VERSION 5.7 ;
  NOWIREEXTENSIONATPIN ON ;
  DIVIDERCHAR "/" ;
  BUSBITCHARS "[]" ;
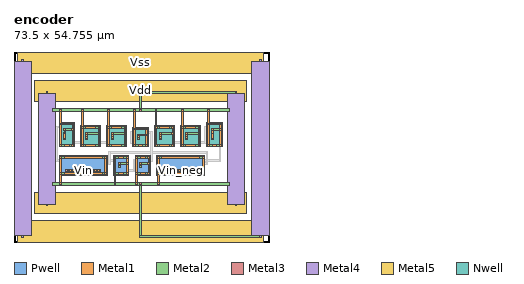
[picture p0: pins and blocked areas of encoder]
MACRO encoder
  CLASS BLOCK ;
  FOREIGN encoder ;
  ORIGIN 0.000 0.000 ;
  SIZE 73.500 BY 54.755 ;
  PIN Vss
    USE GROUND;
    ANTENNADIFFAREA 37.930798 ;
    PORT
      LAYER Pwell ;
        RECT 13.000 19.260 26.860 24.860 ;
        RECT 28.660 19.260 33.100 24.860 ;
        RECT 34.900 19.260 39.340 24.860 ;
        RECT 41.140 19.260 55.000 24.860 ;
      LAYER Metal1 ;
        RECT 13.230 24.150 13.730 24.650 ;
        RECT 14.480 24.150 25.380 24.650 ;
        RECT 26.130 24.150 26.630 24.650 ;
        RECT 13.230 19.970 13.690 24.150 ;
        RECT 26.170 19.970 26.630 24.150 ;
        RECT 13.230 19.470 13.730 19.970 ;
        RECT 14.480 19.470 25.380 19.970 ;
        RECT 26.130 19.470 26.630 19.970 ;
        RECT 28.890 24.150 29.390 24.650 ;
        RECT 30.230 24.150 31.530 24.650 ;
        RECT 32.370 24.150 32.870 24.650 ;
        RECT 28.890 19.970 29.350 24.150 ;
        RECT 32.410 22.955 32.870 24.150 ;
        RECT 30.060 22.455 30.560 22.955 ;
        RECT 32.370 22.455 32.870 22.955 ;
        RECT 30.080 21.905 30.540 22.455 ;
        RECT 30.060 21.405 30.560 21.905 ;
        RECT 32.410 19.970 32.870 22.455 ;
        RECT 28.890 19.470 29.390 19.970 ;
        RECT 30.230 19.470 31.530 19.970 ;
        RECT 32.370 19.470 32.870 19.970 ;
        RECT 35.130 24.150 35.630 24.650 ;
        RECT 36.470 24.150 37.770 24.650 ;
        RECT 38.610 24.150 39.110 24.650 ;
        RECT 35.130 19.970 35.590 24.150 ;
        RECT 38.650 22.955 39.110 24.150 ;
        RECT 36.300 22.455 36.800 22.955 ;
        RECT 38.610 22.455 39.110 22.955 ;
        RECT 36.320 21.905 36.780 22.455 ;
        RECT 36.300 21.405 36.800 21.905 ;
        RECT 38.650 19.970 39.110 22.455 ;
        RECT 35.130 19.470 35.630 19.970 ;
        RECT 36.470 19.470 37.770 19.970 ;
        RECT 38.610 19.470 39.110 19.970 ;
        RECT 41.370 24.150 41.870 24.650 ;
        RECT 42.620 24.150 53.520 24.650 ;
        RECT 54.270 24.150 54.770 24.650 ;
        RECT 41.370 19.970 41.830 24.150 ;
        RECT 54.310 19.970 54.770 24.150 ;
        RECT 41.370 19.470 41.870 19.970 ;
        RECT 42.620 19.470 53.520 19.970 ;
        RECT 54.270 19.470 54.770 19.970 ;
        RECT 13.230 17.010 13.690 19.470 ;
        RECT 28.890 17.010 29.350 19.470 ;
        RECT 35.130 17.010 35.590 19.470 ;
        RECT 41.370 17.010 41.830 19.470 ;
        RECT 13.230 16.510 13.730 17.010 ;
        RECT 28.890 16.510 29.390 17.010 ;
        RECT 35.130 16.510 35.630 17.010 ;
        RECT 41.330 16.510 41.830 17.010 ;
      LAYER Metal2 ;
        RECT 2.250 52.005 2.750 52.505 ;
        RECT 70.750 52.005 71.250 52.505 ;
        RECT 13.230 24.150 26.630 24.650 ;
        RECT 28.890 24.150 32.870 24.650 ;
        RECT 35.130 24.150 39.110 24.650 ;
        RECT 41.370 24.150 54.770 24.650 ;
        RECT 30.060 22.455 32.870 22.955 ;
        RECT 36.300 22.455 39.110 22.955 ;
        RECT 30.060 21.405 30.560 21.905 ;
        RECT 36.300 21.405 36.800 21.905 ;
        RECT 13.230 19.470 26.630 19.970 ;
        RECT 28.890 19.470 32.870 19.970 ;
        RECT 35.130 19.470 39.110 19.970 ;
        RECT 41.370 19.470 54.770 19.970 ;
        RECT 11.000 16.260 62.000 17.260 ;
        RECT 36.250 1.750 36.750 16.260 ;
        RECT 2.250 1.250 2.750 1.750 ;
        RECT 36.250 1.250 71.250 1.750 ;
      LAYER Metal3 ;
        RECT 2.250 52.005 2.750 52.505 ;
        RECT 70.750 52.005 71.250 52.505 ;
        RECT 36.250 16.510 36.750 17.010 ;
        RECT 2.250 1.250 2.750 1.750 ;
        RECT 70.750 1.250 71.250 1.750 ;
      LAYER Metal4 ;
        RECT 2.250 52.005 2.750 52.505 ;
        RECT 70.750 52.005 71.250 52.505 ;
        RECT 0.000 1.750 5.000 52.005 ;
        RECT 68.500 1.750 73.500 52.005 ;
        RECT 2.250 1.250 2.750 1.750 ;
        RECT 70.750 1.250 71.250 1.750 ;
      LAYER Metal5 ;
        RECT 1.000 48.625 72.000 54.755 ;
        RECT 1.000 0.000 72.000 6.130 ;
    END
  END Vss
  PIN Vdd
    USE POWER;
    ANTENNADIFFAREA 54.005398 ;
    PORT
      LAYER Nwell ;
        RECT 13.000 27.405 17.440 34.495 ;
        RECT 19.240 27.405 24.960 33.435 ;
        RECT 26.760 27.405 32.480 33.435 ;
        RECT 34.280 27.405 38.720 33.005 ;
        RECT 40.520 27.405 46.240 33.435 ;
        RECT 48.040 27.405 53.760 33.435 ;
        RECT 55.560 27.405 60.000 34.495 ;
      LAYER Metal1 ;
        RECT 13.230 37.745 13.730 38.245 ;
        RECT 19.470 37.745 19.970 38.245 ;
        RECT 26.990 37.745 27.490 38.245 ;
        RECT 34.510 37.745 35.010 38.245 ;
        RECT 40.710 37.745 41.210 38.245 ;
        RECT 48.230 37.745 48.730 38.245 ;
        RECT 55.750 37.745 56.250 38.245 ;
        RECT 13.230 34.285 13.690 37.745 ;
        RECT 13.230 33.785 13.730 34.285 ;
        RECT 14.570 33.785 15.870 34.285 ;
        RECT 16.710 33.785 17.210 34.285 ;
        RECT 13.230 28.115 13.690 33.785 ;
        RECT 16.750 32.595 17.210 33.785 ;
        RECT 14.400 32.095 14.900 32.595 ;
        RECT 16.710 32.095 17.210 32.595 ;
        RECT 14.420 31.195 14.880 32.095 ;
        RECT 14.400 29.895 14.900 31.195 ;
        RECT 14.420 29.545 14.880 29.895 ;
        RECT 16.750 28.115 17.210 32.095 ;
        RECT 13.230 27.615 13.730 28.115 ;
        RECT 14.570 27.615 15.870 28.115 ;
        RECT 16.710 27.615 17.210 28.115 ;
        RECT 19.470 33.225 19.930 37.745 ;
        RECT 26.990 33.225 27.450 37.745 ;
        RECT 19.470 32.725 19.970 33.225 ;
        RECT 20.650 32.725 23.550 33.225 ;
        RECT 24.230 32.725 24.730 33.225 ;
        RECT 19.470 28.115 19.930 32.725 ;
        RECT 24.270 31.535 24.730 32.725 ;
        RECT 20.640 31.035 21.140 31.535 ;
        RECT 24.230 31.035 24.730 31.535 ;
        RECT 20.660 30.270 21.120 31.035 ;
        RECT 20.640 29.770 21.140 30.270 ;
        RECT 20.660 29.555 21.120 29.770 ;
        RECT 24.270 28.115 24.730 31.035 ;
        RECT 19.470 27.615 19.970 28.115 ;
        RECT 20.650 27.615 23.550 28.115 ;
        RECT 24.230 27.615 24.730 28.115 ;
        RECT 26.990 32.725 27.490 33.225 ;
        RECT 28.170 32.725 31.070 33.225 ;
        RECT 31.750 32.725 32.250 33.225 ;
        RECT 26.990 28.115 27.450 32.725 ;
        RECT 31.790 31.535 32.250 32.725 ;
        RECT 28.160 31.035 28.660 31.535 ;
        RECT 31.750 31.035 32.250 31.535 ;
        RECT 28.180 30.270 28.640 31.035 ;
        RECT 28.160 29.770 28.660 30.270 ;
        RECT 28.180 29.555 28.640 29.770 ;
        RECT 31.790 28.115 32.250 31.035 ;
        RECT 26.990 27.615 27.490 28.115 ;
        RECT 28.170 27.615 31.070 28.115 ;
        RECT 31.750 27.615 32.250 28.115 ;
        RECT 34.510 32.795 34.970 37.745 ;
        RECT 40.750 33.225 41.210 37.745 ;
        RECT 48.270 33.225 48.730 37.745 ;
        RECT 55.790 34.285 56.250 37.745 ;
        RECT 55.790 33.785 56.290 34.285 ;
        RECT 57.130 33.785 58.430 34.285 ;
        RECT 59.270 33.785 59.770 34.285 ;
        RECT 34.510 32.295 35.010 32.795 ;
        RECT 35.850 32.295 37.150 32.795 ;
        RECT 37.990 32.295 38.490 32.795 ;
        RECT 34.510 28.115 34.970 32.295 ;
        RECT 38.030 31.100 38.490 32.295 ;
        RECT 35.680 30.600 36.180 31.100 ;
        RECT 37.990 30.600 38.490 31.100 ;
        RECT 35.700 30.050 36.160 30.600 ;
        RECT 35.680 29.550 36.180 30.050 ;
        RECT 38.030 28.115 38.490 30.600 ;
        RECT 34.510 27.615 35.010 28.115 ;
        RECT 35.850 27.615 37.150 28.115 ;
        RECT 37.990 27.615 38.490 28.115 ;
        RECT 40.750 32.725 41.250 33.225 ;
        RECT 41.930 32.725 44.830 33.225 ;
        RECT 45.510 32.725 46.010 33.225 ;
        RECT 40.750 28.115 41.210 32.725 ;
        RECT 45.550 31.535 46.010 32.725 ;
        RECT 41.920 31.035 42.420 31.535 ;
        RECT 45.510 31.035 46.010 31.535 ;
        RECT 41.940 30.270 42.400 31.035 ;
        RECT 41.920 29.770 42.420 30.270 ;
        RECT 41.940 29.555 42.400 29.770 ;
        RECT 45.550 28.115 46.010 31.035 ;
        RECT 40.750 27.615 41.250 28.115 ;
        RECT 41.930 27.615 44.830 28.115 ;
        RECT 45.510 27.615 46.010 28.115 ;
        RECT 48.270 32.725 48.770 33.225 ;
        RECT 49.450 32.725 52.350 33.225 ;
        RECT 53.030 32.725 53.530 33.225 ;
        RECT 48.270 28.115 48.730 32.725 ;
        RECT 53.070 31.535 53.530 32.725 ;
        RECT 49.440 31.035 49.940 31.535 ;
        RECT 53.030 31.035 53.530 31.535 ;
        RECT 49.460 30.270 49.920 31.035 ;
        RECT 49.440 29.770 49.940 30.270 ;
        RECT 49.460 29.555 49.920 29.770 ;
        RECT 53.070 28.115 53.530 31.035 ;
        RECT 48.270 27.615 48.770 28.115 ;
        RECT 49.450 27.615 52.350 28.115 ;
        RECT 53.030 27.615 53.530 28.115 ;
        RECT 55.790 28.115 56.250 33.785 ;
        RECT 59.310 32.595 59.770 33.785 ;
        RECT 56.960 32.095 57.460 32.595 ;
        RECT 59.270 32.095 59.770 32.595 ;
        RECT 56.980 31.195 57.440 32.095 ;
        RECT 56.960 29.895 57.460 31.195 ;
        RECT 56.980 29.545 57.440 29.895 ;
        RECT 59.310 28.115 59.770 32.095 ;
        RECT 55.790 27.615 56.290 28.115 ;
        RECT 57.130 27.615 58.430 28.115 ;
        RECT 59.270 27.615 59.770 28.115 ;
      LAYER Metal2 ;
        RECT 9.250 42.875 9.750 43.375 ;
        RECT 36.250 42.875 64.250 43.375 ;
        RECT 36.250 38.495 36.750 42.875 ;
        RECT 11.000 37.495 62.000 38.495 ;
        RECT 13.230 33.785 17.210 34.285 ;
        RECT 55.790 33.785 59.770 34.285 ;
        RECT 19.470 32.725 24.730 33.225 ;
        RECT 26.990 32.725 32.250 33.225 ;
        RECT 14.400 32.095 17.210 32.595 ;
        RECT 34.510 32.295 38.490 32.795 ;
        RECT 40.750 32.725 46.010 33.225 ;
        RECT 48.270 32.725 53.530 33.225 ;
        RECT 56.960 32.095 59.770 32.595 ;
        RECT 14.400 29.545 14.900 31.545 ;
        RECT 20.640 31.035 24.730 31.535 ;
        RECT 28.160 31.035 32.250 31.535 ;
        RECT 35.680 30.600 38.490 31.100 ;
        RECT 41.920 31.035 46.010 31.535 ;
        RECT 49.440 31.035 53.530 31.535 ;
        RECT 20.640 29.555 21.140 30.485 ;
        RECT 28.160 29.555 28.660 30.485 ;
        RECT 35.680 29.550 36.180 30.050 ;
        RECT 41.920 29.555 42.420 30.485 ;
        RECT 49.440 29.555 49.940 30.485 ;
        RECT 56.960 29.545 57.460 31.545 ;
        RECT 13.230 27.615 17.210 28.115 ;
        RECT 19.470 27.615 24.730 28.115 ;
        RECT 26.990 27.615 32.250 28.115 ;
        RECT 34.510 27.615 38.490 28.115 ;
        RECT 40.750 27.615 46.010 28.115 ;
        RECT 48.270 27.615 53.530 28.115 ;
        RECT 55.790 27.615 59.770 28.115 ;
        RECT 9.250 10.380 9.750 10.880 ;
        RECT 63.750 10.380 64.250 10.880 ;
      LAYER Metal3 ;
        RECT 9.250 42.875 9.750 43.375 ;
        RECT 63.750 42.875 64.250 43.375 ;
        RECT 36.250 37.745 36.750 38.245 ;
        RECT 9.250 10.380 9.750 10.880 ;
        RECT 63.750 10.380 64.250 10.880 ;
      LAYER Metal4 ;
        RECT 9.250 42.875 9.750 43.375 ;
        RECT 63.750 42.875 64.250 43.375 ;
        RECT 7.000 10.875 12.000 42.875 ;
        RECT 61.500 10.875 66.500 42.875 ;
        RECT 9.250 10.380 9.750 10.875 ;
        RECT 63.750 10.380 64.250 10.875 ;
      LAYER Metal5 ;
        RECT 6.000 40.495 67.000 46.625 ;
        RECT 6.000 8.130 67.000 14.260 ;
    END
  END Vdd
  PIN Vin
    ANTENNAGATEAREA 5.000000 ;
    PORT
      LAYER Metal1 ;
        RECT 15.280 20.365 15.780 20.865 ;
        RECT 16.080 20.365 16.580 20.865 ;
        RECT 16.880 20.365 17.380 20.865 ;
        RECT 17.680 20.365 18.180 20.865 ;
        RECT 18.480 20.365 18.980 20.865 ;
        RECT 19.280 20.365 19.780 20.865 ;
        RECT 20.080 20.365 20.580 20.865 ;
        RECT 20.880 20.365 21.380 20.865 ;
        RECT 21.680 20.365 22.180 20.865 ;
        RECT 22.480 20.365 22.980 20.865 ;
        RECT 23.280 20.365 23.780 20.865 ;
        RECT 24.080 20.365 24.580 20.865 ;
      LAYER Metal2 ;
        RECT 14.930 20.365 24.930 20.865 ;
      LAYER Metal3 ;
        RECT 14.930 20.365 15.430 20.865 ;
    END
  END Vin
  PIN Vin_neg
    ANTENNAGATEAREA 5.000000 ;
    PORT
      LAYER Metal1 ;
        RECT 43.420 20.365 43.920 20.865 ;
        RECT 44.220 20.365 44.720 20.865 ;
        RECT 45.020 20.365 45.520 20.865 ;
        RECT 45.820 20.365 46.320 20.865 ;
        RECT 46.620 20.365 47.120 20.865 ;
        RECT 47.420 20.365 47.920 20.865 ;
        RECT 48.220 20.365 48.720 20.865 ;
        RECT 49.020 20.365 49.520 20.865 ;
        RECT 49.820 20.365 50.320 20.865 ;
        RECT 50.620 20.365 51.120 20.865 ;
        RECT 51.420 20.365 51.920 20.865 ;
        RECT 52.220 20.365 52.720 20.865 ;
      LAYER Metal2 ;
        RECT 43.070 20.365 53.070 20.865 ;
      LAYER Metal3 ;
        RECT 43.070 20.365 43.570 20.865 ;
    END
  END Vin_neg
  OBS
      LAYER Metal1 ;
        RECT 15.540 32.895 16.040 33.395 ;
        RECT 58.100 32.895 58.600 33.395 ;
        RECT 15.560 31.195 16.020 32.895 ;
        RECT 23.060 31.835 23.560 32.335 ;
        RECT 30.580 31.835 31.080 32.335 ;
        RECT 15.540 29.895 16.040 31.195 ;
        RECT 23.080 30.270 23.540 31.835 ;
        RECT 30.600 30.270 31.060 31.835 ;
        RECT 36.820 31.400 37.320 31.900 ;
        RECT 44.340 31.835 44.840 32.335 ;
        RECT 51.860 31.835 52.360 32.335 ;
        RECT 15.560 29.545 16.020 29.895 ;
        RECT 23.060 29.770 23.560 30.270 ;
        RECT 30.580 29.770 31.080 30.270 ;
        RECT 36.840 30.050 37.300 31.400 ;
        RECT 44.360 30.270 44.820 31.835 ;
        RECT 51.880 30.270 52.340 31.835 ;
        RECT 58.120 31.195 58.580 32.895 ;
        RECT 23.080 29.555 23.540 29.770 ;
        RECT 30.600 29.555 31.060 29.770 ;
        RECT 36.820 29.550 37.320 30.050 ;
        RECT 44.340 29.770 44.840 30.270 ;
        RECT 51.860 29.770 52.360 30.270 ;
        RECT 58.100 29.895 58.600 31.195 ;
        RECT 44.360 29.555 44.820 29.770 ;
        RECT 51.880 29.555 52.340 29.770 ;
        RECT 58.120 29.545 58.580 29.895 ;
        RECT 14.970 28.505 15.470 29.005 ;
        RECT 21.450 28.510 21.950 29.010 ;
        RECT 22.250 28.510 22.750 29.010 ;
        RECT 28.970 28.510 29.470 29.010 ;
        RECT 29.770 28.510 30.270 29.010 ;
        RECT 36.250 28.510 36.750 29.010 ;
        RECT 42.730 28.510 43.230 29.010 ;
        RECT 43.530 28.510 44.030 29.010 ;
        RECT 50.250 28.510 50.750 29.010 ;
        RECT 51.050 28.510 51.550 29.010 ;
        RECT 57.530 28.505 58.030 29.005 ;
        RECT 24.960 23.255 25.460 23.755 ;
        RECT 31.200 23.255 31.700 23.755 ;
        RECT 37.440 23.255 37.940 23.755 ;
        RECT 53.100 23.255 53.600 23.755 ;
        RECT 14.400 22.455 14.900 22.955 ;
        RECT 14.420 21.905 14.880 22.455 ;
        RECT 24.980 21.905 25.440 23.255 ;
        RECT 31.220 21.905 31.680 23.255 ;
        RECT 37.460 21.905 37.920 23.255 ;
        RECT 42.540 22.455 43.040 22.955 ;
        RECT 42.560 21.905 43.020 22.455 ;
        RECT 53.120 21.905 53.580 23.255 ;
        RECT 14.400 21.405 14.900 21.905 ;
        RECT 24.960 21.405 25.460 21.905 ;
        RECT 31.200 21.405 31.700 21.905 ;
        RECT 37.440 21.405 37.940 21.905 ;
        RECT 42.540 21.405 43.040 21.905 ;
        RECT 53.100 21.405 53.600 21.905 ;
        RECT 30.630 20.365 31.130 20.865 ;
        RECT 36.870 20.365 37.370 20.865 ;
      LAYER Metal2 ;
        RECT 11.900 32.895 17.040 33.395 ;
        RECT 54.960 32.895 59.600 33.395 ;
        RECT 20.640 31.835 23.560 32.335 ;
        RECT 28.160 31.835 31.080 32.335 ;
        RECT 15.540 29.545 16.040 31.545 ;
        RECT 33.680 31.400 39.940 31.900 ;
        RECT 41.920 31.835 44.840 32.335 ;
        RECT 49.440 31.835 52.360 32.335 ;
        RECT 23.060 29.555 23.560 30.485 ;
        RECT 30.580 29.555 31.080 30.485 ;
        RECT 36.820 29.550 37.320 30.050 ;
        RECT 44.340 29.555 44.840 30.485 ;
        RECT 51.860 29.555 52.360 30.485 ;
        RECT 58.100 29.545 58.600 31.545 ;
        RECT 21.170 29.005 30.550 29.010 ;
        RECT 14.970 28.510 30.550 29.005 ;
        RECT 33.680 28.510 36.750 29.010 ;
        RECT 42.450 29.005 57.530 29.010 ;
        RECT 42.450 28.510 58.030 29.005 ;
        RECT 14.970 28.505 21.170 28.510 ;
        RECT 54.960 28.505 58.030 28.510 ;
        RECT 27.210 25.455 55.850 25.955 ;
        RECT 11.900 23.255 25.460 23.755 ;
        RECT 27.210 23.255 31.700 23.755 ;
        RECT 34.300 23.255 39.940 23.755 ;
        RECT 42.540 23.255 59.600 23.755 ;
        RECT 14.400 22.455 27.710 22.955 ;
        RECT 42.540 22.455 55.850 22.955 ;
        RECT 14.400 21.405 14.900 21.905 ;
        RECT 24.960 21.405 25.460 21.905 ;
        RECT 31.200 21.405 31.700 21.905 ;
        RECT 37.440 21.405 37.940 21.905 ;
        RECT 42.540 21.405 43.040 21.905 ;
        RECT 53.100 21.405 53.600 21.905 ;
        RECT 30.630 20.365 37.370 20.865 ;
      LAYER Metal3 ;
        RECT 11.900 23.255 12.400 33.395 ;
        RECT 16.540 28.505 17.040 33.395 ;
        RECT 22.100 31.835 22.600 32.335 ;
        RECT 29.620 31.835 30.120 32.335 ;
        RECT 33.680 28.510 34.180 31.900 ;
        RECT 27.210 22.455 27.710 25.955 ;
        RECT 34.300 20.365 34.800 23.755 ;
        RECT 39.440 23.255 39.940 31.900 ;
        RECT 43.380 31.835 43.880 32.335 ;
        RECT 50.900 31.835 51.400 32.335 ;
        RECT 54.960 28.505 55.460 33.395 ;
        RECT 55.350 22.455 55.850 25.955 ;
        RECT 59.100 23.255 59.600 33.395 ;
  END
END encoder
END LIBRARY

